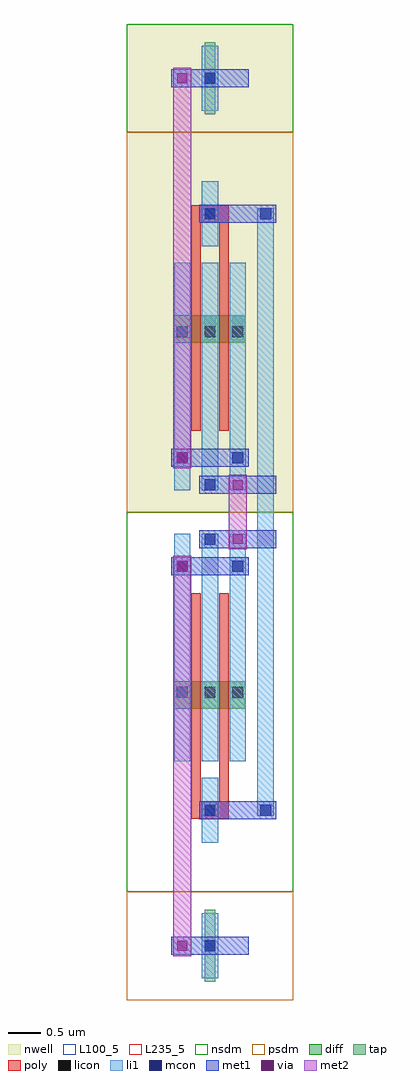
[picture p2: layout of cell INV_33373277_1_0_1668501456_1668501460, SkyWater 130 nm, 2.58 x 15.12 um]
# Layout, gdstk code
from math import pi, radians
import gdstk
lib = gdstk.Library(unit=1e-6, precision=1e-09)
def R(c, l, rs):  # rectangles x0, y0, x1, y1
    for r in rs: c.add(gdstk.rectangle(r[:2], r[2:], *l))
def A(c, l, x, y, w, h, nx, ny, dx, dy):  # array of equal rectangles
    R(c, l, [(x+i*dx, y+j*dy, x+i*dx+w, y+j*dy+h) for i in range(nx) for j in range(ny)])
def P(c, l, *ps):  # polygons
    for p in ps: c.add(gdstk.Polygon(p, *l))
nwell = (64, 20)
diff = (65, 20)
tap = (65, 44)
poly = (66, 20)
licon = (66, 44)
li1 = (67, 20)
mcon = (67, 44)
met1 = (68, 20)
via = (68, 44)
met2 = (69, 20)
nsdm = (93, 44)
psdm = (94, 20)
L100_5 = (100, 5)
L235_5 = (235, 5)

nmos_s_96839798_x1_y1_16 = lib.new_cell('NMOS_S_96839798_X1_Y1_1668501455_1668501456_1668501460')
R(nmos_s_96839798_x1_y1_16, diff, [(0.735,2.625,1.845,3.045)])
R(nmos_s_96839798_x1_y1_16, tap, [(1.205,6.16,1.375,7.28)])
R(nmos_s_96839798_x1_y1_16, poly, [(1,1.26,1.15,4.62), (1.43,1.26,1.58,4.62), (1,4.485,1.58,4.755)])
A(nmos_s_96839798_x1_y1_16, licon, 0.775, 2.705, 0.17, 0.17, 3, 1, 0.43, 0)
R(nmos_s_96839798_x1_y1_16, licon, [(1.205,4.535,1.375,4.705), (1.205,6.635,1.375,6.805)])
A(nmos_s_96839798_x1_y1_16, li1, 0.735, 0.335, 0.25, 3.53, 3, 1, 0.43, 0)
R(nmos_s_96839798_x1_y1_16, li1, [(1.165,4.115,1.415,5.125), (1.165,6.215,1.415,7.225)])
R(nmos_s_96839798_x1_y1_16, mcon, [(1.205,0.335,1.375,0.505), (0.775,0.755,0.945,0.925), (1.635,0.755,1.805,0.925), (1.205,4.535,1.375,4.705), (1.205,6.635,1.375,6.805)])
R(nmos_s_96839798_x1_y1_16, met1, [(0.26,0.28,1.46,0.56), (0.69,0.7,1.89,0.98), (0.26,4.48,1.46,4.76), (0.69,6.58,1.89,6.86)])
R(nmos_s_96839798_x1_y1_16, via, [(1.645,0.765,1.795,0.915), (1.645,6.645,1.795,6.795)])
R(nmos_s_96839798_x1_y1_16, met2, [(1.58,0.68,1.86,6.88)])
R(nmos_s_96839798_x1_y1_16, nsdm, [(0,0,2.58,5.88)])
R(nmos_s_96839798_x1_y1_16, psdm, [(0,5.88,2.58,7.56)])
R(nmos_s_96839798_x1_y1_16, L100_5, [(0,0,2.58,7.56)])

pmos_s_48783884_x1_y1_16 = lib.new_cell('PMOS_S_48783884_X1_Y1_1668501456_1668501456_1668501460')
R(pmos_s_48783884_x1_y1_16, nwell, [(0,0,2.58,7.56)])
R(pmos_s_48783884_x1_y1_16, diff, [(0.735,2.625,1.845,3.045)])
R(pmos_s_48783884_x1_y1_16, tap, [(1.205,6.16,1.375,7.28)])
R(pmos_s_48783884_x1_y1_16, poly, [(1,1.26,1.15,4.62), (1.43,1.26,1.58,4.62), (1,4.485,1.58,4.755)])
A(pmos_s_48783884_x1_y1_16, licon, 0.775, 2.705, 0.17, 0.17, 3, 1, 0.43, 0)
R(pmos_s_48783884_x1_y1_16, licon, [(1.205,4.535,1.375,4.705), (1.205,6.635,1.375,6.805)])
A(pmos_s_48783884_x1_y1_16, li1, 0.735, 0.335, 0.25, 3.53, 3, 1, 0.43, 0)
R(pmos_s_48783884_x1_y1_16, li1, [(1.165,4.115,1.415,5.125), (1.165,6.215,1.415,7.225)])
R(pmos_s_48783884_x1_y1_16, mcon, [(1.205,0.335,1.375,0.505), (0.775,0.755,0.945,0.925), (1.635,0.755,1.805,0.925), (1.205,4.535,1.375,4.705), (1.205,6.635,1.375,6.805)])
R(pmos_s_48783884_x1_y1_16, met1, [(0.26,0.28,1.46,0.56), (0.69,0.7,1.89,0.98), (0.26,4.48,1.46,4.76), (0.69,6.58,1.89,6.86)])
R(pmos_s_48783884_x1_y1_16, via, [(1.645,0.765,1.795,0.915), (1.645,6.645,1.795,6.795)])
R(pmos_s_48783884_x1_y1_16, met2, [(1.58,0.68,1.86,6.88)])
R(pmos_s_48783884_x1_y1_16, nsdm, [(0,5.88,2.58,7.56)])
R(pmos_s_48783884_x1_y1_16, psdm, [(0,0,2.58,5.88)])
R(pmos_s_48783884_x1_y1_16, L100_5, [(0,0,2.58,7.56)])

inv_33373277_1_0_1668501 = lib.new_cell('INV_33373277_1_0_1668501456_1668501460')
R(inv_33373277_1_0_1668501, li1, [(2.025,2.855,2.275,3.025), (2.025,2.855,2.275,3.025), (2.025,2.94,2.275,12.18), (2.025,12.095,2.275,12.265), (2.025,12.095,2.275,12.265)])
R(inv_33373277_1_0_1668501, mcon, [(2.065,2.855,2.235,3.025), (2.065,2.855,2.235,3.025), (2.065,12.095,2.235,12.265), (2.065,12.095,2.235,12.265)])
R(inv_33373277_1_0_1668501, met1, [(1.98,2.8,2.32,3.08), (1.98,2.8,2.32,3.08), (1.56,7,1.88,7.28), (1.56,7,1.88,7.28), (1.56,7.84,1.88,8.12), (1.56,7.84,1.88,8.12), (1.98,12.04,2.32,12.32), (1.98,12.04,2.32,12.32)])
P(inv_33373277_1_0_1668501, met1, [(0,0),(0,0),(0,0),(0,0)],
  [(0,0),(0,0),(0,0),(0,0)],
  [(0,0),(0,0),(0,0),(0,0)],
  [(0,0),(0,0),(0,0),(0,0)])
R(inv_33373277_1_0_1668501, via, [(1.645,7.065,1.795,7.215), (1.645,7.065,1.795,7.215), (1.645,7.905,1.795,8.055), (1.645,7.905,1.795,8.055)])
R(inv_33373277_1_0_1668501, met2, [(1.58,6.98,1.86,7.3), (1.58,6.98,1.86,7.3), (1.58,7.14,1.86,7.98), (1.58,7.82,1.86,8.14), (1.58,7.82,1.86,8.14)])
P(inv_33373277_1_0_1668501, met2, [(0,0),(0,0),(0,0),(0,0)],
  [(0,0),(0,0),(0,0),(0,0)])
R(inv_33373277_1_0_1668501, L235_5, [(0,0,2.58,15.12)])
inv_33373277_1_0_1668501.add(gdstk.Reference(nmos_s_96839798_x1_y1_16, (2.58,7.56), rotation=pi))
inv_33373277_1_0_1668501.add(gdstk.Reference(pmos_s_48783884_x1_y1_16, (2.58,7.56), rotation=pi, x_reflection=True))

lib.write_gds('INV_33373277_1_0_1668501456_1668501460.gds')
